VERSION 5.7 ;
  NOWIREEXTENSIONATPIN ON ;
  DIVIDERCHAR "/" ;
  BUSBITCHARS "[]" ;
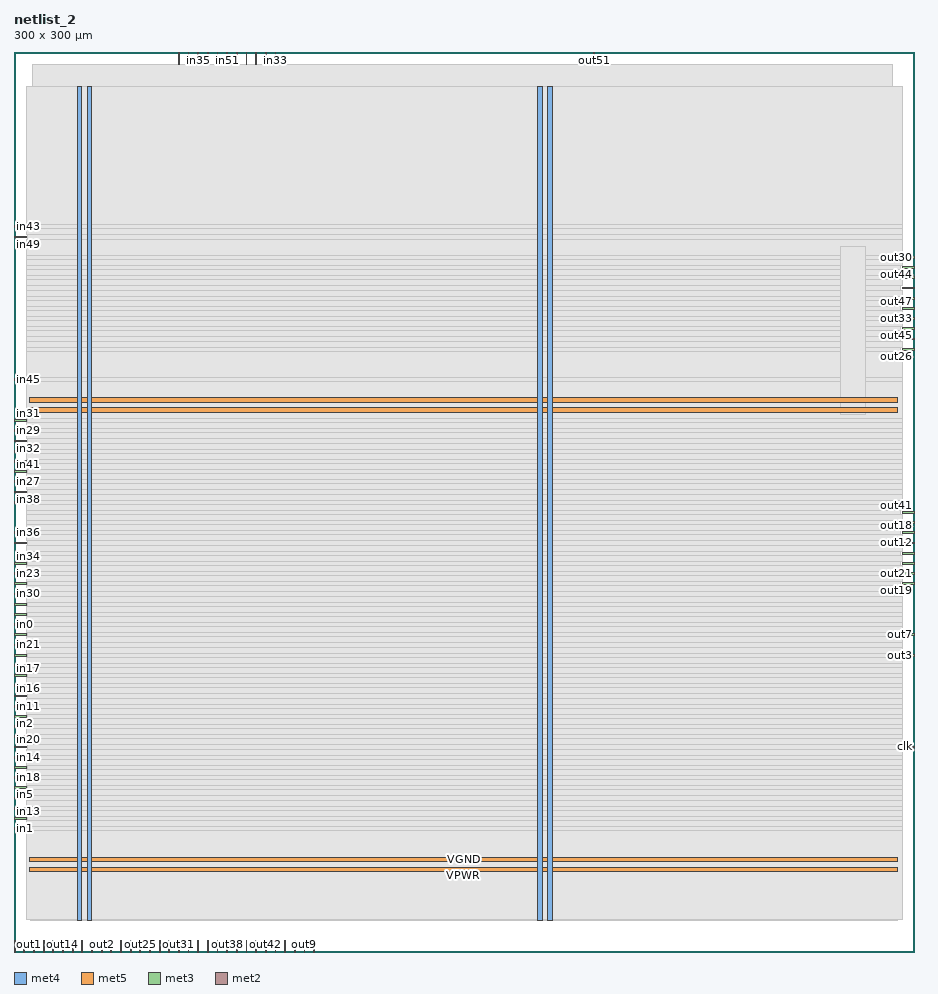
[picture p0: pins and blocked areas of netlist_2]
MACRO netlist_2
  CLASS BLOCK ;
  FOREIGN netlist_2 ;
  ORIGIN 0.000 0.000 ;
  SIZE 300.000 BY 300.000 ;
  PIN VGND
    DIRECTION INOUT ;
    USE GROUND ;
    PORT
      LAYER met4 ;
        RECT 24.340 10.640 25.940 288.560 ;
    END
    PORT
      LAYER met4 ;
        RECT 177.940 10.640 179.540 288.560 ;
    END
    PORT
      LAYER met5 ;
        RECT 5.280 30.030 294.640 31.630 ;
    END
    PORT
      LAYER met5 ;
        RECT 5.280 183.210 294.640 184.810 ;
    END
  END VGND
  PIN VPWR
    DIRECTION INOUT ;
    USE POWER ;
    PORT
      LAYER met4 ;
        RECT 21.040 10.640 22.640 288.560 ;
    END
    PORT
      LAYER met4 ;
        RECT 174.640 10.640 176.240 288.560 ;
    END
    PORT
      LAYER met5 ;
        RECT 5.280 26.730 294.640 28.330 ;
    END
    PORT
      LAYER met5 ;
        RECT 5.280 179.910 294.640 181.510 ;
    END
  END VPWR
  PIN clk
    DIRECTION INPUT ;
    USE SIGNAL ;
    ANTENNAGATEAREA 0.852000 ;
    ANTENNADIFFAREA 0.434700 ;
    PORT
      LAYER met3 ;
        RECT 296.000 68.040 300.000 68.640 ;
    END
  END clk
  PIN in0
    DIRECTION INPUT ;
    USE SIGNAL ;
    ANTENNAGATEAREA 0.196500 ;
    ANTENNADIFFAREA 0.434700 ;
    PORT
      LAYER met3 ;
        RECT 0.000 108.840 4.000 109.440 ;
    END
  END in0
  PIN in1
    DIRECTION INPUT ;
    USE SIGNAL ;
    ANTENNAGATEAREA 0.196500 ;
    ANTENNADIFFAREA 0.434700 ;
    PORT
      LAYER met3 ;
        RECT 0.000 40.840 4.000 41.440 ;
    END
  END in1
  PIN in10
    DIRECTION INPUT ;
    USE SIGNAL ;
    ANTENNAGATEAREA 0.196500 ;
    ANTENNADIFFAREA 0.434700 ;
    PORT
      LAYER met3 ;
        RECT 0.000 71.440 4.000 72.040 ;
    END
  END in10
  PIN in11
    DIRECTION INPUT ;
    USE SIGNAL ;
    ANTENNAGATEAREA 0.196500 ;
    ANTENNADIFFAREA 0.434700 ;
    PORT
      LAYER met3 ;
        RECT 0.000 81.640 4.000 82.240 ;
    END
  END in11
  PIN in12
    DIRECTION INPUT ;
    USE SIGNAL ;
    ANTENNAGATEAREA 0.196500 ;
    ANTENNADIFFAREA 0.434700 ;
    PORT
      LAYER met3 ;
        RECT 0.000 105.440 4.000 106.040 ;
    END
  END in12
  PIN in13
    DIRECTION INPUT ;
    USE SIGNAL ;
    ANTENNAGATEAREA 0.196500 ;
    ANTENNADIFFAREA 0.434700 ;
    PORT
      LAYER met3 ;
        RECT 0.000 44.240 4.000 44.840 ;
    END
  END in13
  PIN in14
    DIRECTION INPUT ;
    USE SIGNAL ;
    ANTENNAGATEAREA 0.196500 ;
    ANTENNADIFFAREA 0.434700 ;
    PORT
      LAYER met3 ;
        RECT 0.000 64.640 4.000 65.240 ;
    END
  END in14
  PIN in15
    DIRECTION INPUT ;
    USE SIGNAL ;
    ANTENNAGATEAREA 0.196500 ;
    ANTENNADIFFAREA 0.434700 ;
    PORT
      LAYER met3 ;
        RECT 0.000 88.440 4.000 89.040 ;
    END
  END in15
  PIN in16
    DIRECTION INPUT ;
    USE SIGNAL ;
    ANTENNAGATEAREA 0.196500 ;
    ANTENNADIFFAREA 0.434700 ;
    PORT
      LAYER met3 ;
        RECT 0.000 85.040 4.000 85.640 ;
    END
  END in16
  PIN in17
    DIRECTION INPUT ;
    USE SIGNAL ;
    ANTENNAGATEAREA 0.196500 ;
    ANTENNADIFFAREA 0.434700 ;
    PORT
      LAYER met3 ;
        RECT 0.000 91.840 4.000 92.440 ;
    END
  END in17
  PIN in18
    DIRECTION INPUT ;
    USE SIGNAL ;
    ANTENNAGATEAREA 0.196500 ;
    ANTENNADIFFAREA 0.434700 ;
    PORT
      LAYER met3 ;
        RECT 0.000 57.840 4.000 58.440 ;
    END
  END in18
  PIN in19
    DIRECTION INPUT ;
    USE SIGNAL ;
    ANTENNAGATEAREA 0.196500 ;
    ANTENNADIFFAREA 0.434700 ;
    PORT
      LAYER met3 ;
        RECT 0.000 61.240 4.000 61.840 ;
    END
  END in19
  PIN in2
    DIRECTION INPUT ;
    USE SIGNAL ;
    ANTENNAGATEAREA 0.196500 ;
    ANTENNADIFFAREA 0.434700 ;
    PORT
      LAYER met3 ;
        RECT 0.000 78.240 4.000 78.840 ;
    END
  END in2
  PIN in20
    DIRECTION INPUT ;
    USE SIGNAL ;
    ANTENNAGATEAREA 0.196500 ;
    ANTENNADIFFAREA 0.434700 ;
    PORT
      LAYER met3 ;
        RECT 0.000 68.040 4.000 68.640 ;
    END
  END in20
  PIN in21
    DIRECTION INPUT ;
    USE SIGNAL ;
    ANTENNAGATEAREA 0.196500 ;
    ANTENNADIFFAREA 0.434700 ;
    PORT
      LAYER met3 ;
        RECT 0.000 102.040 4.000 102.640 ;
    END
  END in21
  PIN in22
    DIRECTION INPUT ;
    USE SIGNAL ;
    ANTENNAGATEAREA 0.196500 ;
    ANTENNADIFFAREA 0.434700 ;
    PORT
      LAYER met3 ;
        RECT 0.000 122.440 4.000 123.040 ;
    END
  END in22
  PIN in23
    DIRECTION INPUT ;
    USE SIGNAL ;
    ANTENNAGATEAREA 0.196500 ;
    ANTENNADIFFAREA 0.434700 ;
    PORT
      LAYER met3 ;
        RECT 0.000 125.840 4.000 126.440 ;
    END
  END in23
  PIN in24
    DIRECTION INPUT ;
    USE SIGNAL ;
    ANTENNAGATEAREA 0.196500 ;
    ANTENNADIFFAREA 0.434700 ;
    PORT
      LAYER met2 ;
        RECT 74.150 296.000 74.430 300.000 ;
    END
  END in24
  PIN in25
    DIRECTION INPUT ;
    USE SIGNAL ;
    ANTENNAGATEAREA 0.196500 ;
    ANTENNADIFFAREA 0.434700 ;
    PORT
      LAYER met3 ;
        RECT 0.000 166.640 4.000 167.240 ;
    END
  END in25
  PIN in26
    DIRECTION INPUT ;
    USE SIGNAL ;
    ANTENNAGATEAREA 0.196500 ;
    ANTENNADIFFAREA 0.434700 ;
    PORT
      LAYER met3 ;
        RECT 0.000 112.240 4.000 112.840 ;
    END
  END in26
  PIN in27
    DIRECTION INPUT ;
    USE SIGNAL ;
    ANTENNAGATEAREA 0.196500 ;
    ANTENNADIFFAREA 0.434700 ;
    PORT
      LAYER met3 ;
        RECT 0.000 156.440 4.000 157.040 ;
    END
  END in27
  PIN in28
    DIRECTION INPUT ;
    USE SIGNAL ;
    ANTENNAGATEAREA 0.196500 ;
    ANTENNADIFFAREA 0.434700 ;
    PORT
      LAYER met3 ;
        RECT 0.000 149.640 4.000 150.240 ;
    END
  END in28
  PIN in29
    DIRECTION INPUT ;
    USE SIGNAL ;
    ANTENNAGATEAREA 0.196500 ;
    ANTENNADIFFAREA 0.434700 ;
    PORT
      LAYER met3 ;
        RECT 0.000 173.440 4.000 174.040 ;
    END
  END in29
  PIN in3
    DIRECTION INPUT ;
    USE SIGNAL ;
    ANTENNAGATEAREA 0.196500 ;
    ANTENNADIFFAREA 0.434700 ;
    PORT
      LAYER met3 ;
        RECT 0.000 98.640 4.000 99.240 ;
    END
  END in3
  PIN in30
    DIRECTION INPUT ;
    USE SIGNAL ;
    ANTENNAGATEAREA 0.196500 ;
    ANTENNADIFFAREA 0.434700 ;
    PORT
      LAYER met3 ;
        RECT 0.000 119.040 4.000 119.640 ;
    END
  END in30
  PIN in31
    DIRECTION INPUT ;
    USE SIGNAL ;
    ANTENNAGATEAREA 0.196500 ;
    ANTENNADIFFAREA 0.434700 ;
    PORT
      LAYER met3 ;
        RECT 0.000 176.840 4.000 177.440 ;
    END
  END in31
  PIN in32
    DIRECTION INPUT ;
    USE SIGNAL ;
    ANTENNAGATEAREA 0.196500 ;
    ANTENNADIFFAREA 0.434700 ;
    PORT
      LAYER met3 ;
        RECT 0.000 170.040 4.000 170.640 ;
    END
  END in32
  PIN in33
    DIRECTION INPUT ;
    USE SIGNAL ;
    ANTENNAGATEAREA 0.196500 ;
    ANTENNADIFFAREA 0.434700 ;
    PORT
      LAYER met2 ;
        RECT 87.030 296.000 87.310 300.000 ;
    END
  END in33
  PIN in34
    DIRECTION INPUT ;
    USE SIGNAL ;
    ANTENNAGATEAREA 0.196500 ;
    ANTENNADIFFAREA 0.434700 ;
    PORT
      LAYER met3 ;
        RECT 0.000 129.240 4.000 129.840 ;
    END
  END in34
  PIN in35
    DIRECTION INPUT ;
    USE SIGNAL ;
    ANTENNAGATEAREA 0.196500 ;
    ANTENNADIFFAREA 0.434700 ;
    PORT
      LAYER met2 ;
        RECT 61.270 296.000 61.550 300.000 ;
    END
  END in35
  PIN in36
    DIRECTION INPUT ;
    USE SIGNAL ;
    ANTENNAGATEAREA 0.196500 ;
    ANTENNADIFFAREA 0.434700 ;
    PORT
      LAYER met3 ;
        RECT 0.000 139.440 4.000 140.040 ;
    END
  END in36
  PIN in37
    DIRECTION INPUT ;
    USE SIGNAL ;
    ANTENNAGATEAREA 0.196500 ;
    ANTENNADIFFAREA 0.434700 ;
    PORT
      LAYER met3 ;
        RECT 0.000 115.640 4.000 116.240 ;
    END
  END in37
  PIN in38
    DIRECTION INPUT ;
    USE SIGNAL ;
    ANTENNAGATEAREA 0.196500 ;
    ANTENNADIFFAREA 0.434700 ;
    PORT
      LAYER met3 ;
        RECT 0.000 153.040 4.000 153.640 ;
    END
  END in38
  PIN in39
    DIRECTION INPUT ;
    USE SIGNAL ;
    ANTENNAGATEAREA 0.196500 ;
    ANTENNADIFFAREA 0.434700 ;
    PORT
      LAYER met2 ;
        RECT 58.050 296.000 58.330 300.000 ;
    END
  END in39
  PIN in4
    DIRECTION INPUT ;
    USE SIGNAL ;
    ANTENNAGATEAREA 0.196500 ;
    ANTENNADIFFAREA 0.434700 ;
    PORT
      LAYER met3 ;
        RECT 0.000 74.840 4.000 75.440 ;
    END
  END in4
  PIN in40
    DIRECTION INPUT ;
    USE SIGNAL ;
    ANTENNAGATEAREA 0.196500 ;
    ANTENNADIFFAREA 0.434700 ;
    PORT
      LAYER met3 ;
        RECT 0.000 163.240 4.000 163.840 ;
    END
  END in40
  PIN in41
    DIRECTION INPUT ;
    USE SIGNAL ;
    ANTENNAGATEAREA 0.196500 ;
    ANTENNADIFFAREA 0.434700 ;
    PORT
      LAYER met3 ;
        RECT 0.000 159.840 4.000 160.440 ;
    END
  END in41
  PIN in42
    DIRECTION INPUT ;
    USE SIGNAL ;
    ANTENNAGATEAREA 0.196500 ;
    ANTENNADIFFAREA 0.434700 ;
    PORT
      LAYER met3 ;
        RECT 0.000 136.040 4.000 136.640 ;
    END
  END in42
  PIN in43
    DIRECTION INPUT ;
    USE SIGNAL ;
    ANTENNAGATEAREA 0.196500 ;
    ANTENNADIFFAREA 0.434700 ;
    PORT
      LAYER met3 ;
        RECT 0.000 241.440 4.000 242.040 ;
    END
  END in43
  PIN in44
    DIRECTION INPUT ;
    USE SIGNAL ;
    ANTENNAGATEAREA 0.196500 ;
    ANTENNADIFFAREA 0.434700 ;
    PORT
      LAYER met2 ;
        RECT 80.590 296.000 80.870 300.000 ;
    END
  END in44
  PIN in45
    DIRECTION INPUT ;
    USE SIGNAL ;
    ANTENNAGATEAREA 0.196500 ;
    ANTENNADIFFAREA 0.434700 ;
    PORT
      LAYER met3 ;
        RECT 0.000 190.440 4.000 191.040 ;
    END
  END in45
  PIN in46
    DIRECTION INPUT ;
    USE SIGNAL ;
    ANTENNAGATEAREA 0.159000 ;
    ANTENNADIFFAREA 0.434700 ;
    PORT
      LAYER met2 ;
        RECT 67.710 296.000 67.990 300.000 ;
    END
  END in46
  PIN in47
    DIRECTION INPUT ;
    USE SIGNAL ;
    ANTENNAGATEAREA 0.213000 ;
    ANTENNADIFFAREA 0.434700 ;
    PORT
      LAYER met2 ;
        RECT 77.370 296.000 77.650 300.000 ;
    END
  END in47
  PIN in48
    DIRECTION INPUT ;
    USE SIGNAL ;
    ANTENNAGATEAREA 0.213000 ;
    ANTENNADIFFAREA 0.434700 ;
    PORT
      LAYER met2 ;
        RECT 54.830 296.000 55.110 300.000 ;
    END
  END in48
  PIN in49
    DIRECTION INPUT ;
    USE SIGNAL ;
    ANTENNAGATEAREA 0.196500 ;
    ANTENNADIFFAREA 0.434700 ;
    PORT
      LAYER met3 ;
        RECT 0.000 238.040 4.000 238.640 ;
    END
  END in49
  PIN in5
    DIRECTION INPUT ;
    USE SIGNAL ;
    ANTENNAGATEAREA 0.196500 ;
    ANTENNADIFFAREA 0.434700 ;
    PORT
      LAYER met3 ;
        RECT 0.000 54.440 4.000 55.040 ;
    END
  END in5
  PIN in50
    DIRECTION INPUT ;
    USE SIGNAL ;
    ANTENNAGATEAREA 0.196500 ;
    ANTENNADIFFAREA 0.434700 ;
    PORT
      LAYER met2 ;
        RECT 64.490 296.000 64.770 300.000 ;
    END
  END in50
  PIN in51
    DIRECTION INPUT ;
    USE SIGNAL ;
    ANTENNAGATEAREA 0.196500 ;
    ANTENNADIFFAREA 0.434700 ;
    PORT
      LAYER met2 ;
        RECT 70.930 296.000 71.210 300.000 ;
    END
  END in51
  PIN in6
    DIRECTION INPUT ;
    USE SIGNAL ;
    ANTENNAGATEAREA 0.196500 ;
    ANTENNADIFFAREA 0.434700 ;
    PORT
      LAYER met3 ;
        RECT 0.000 47.640 4.000 48.240 ;
    END
  END in6
  PIN in7
    DIRECTION INPUT ;
    USE SIGNAL ;
    ANTENNAGATEAREA 0.196500 ;
    ANTENNADIFFAREA 0.434700 ;
    PORT
      LAYER met3 ;
        RECT 0.000 51.040 4.000 51.640 ;
    END
  END in7
  PIN in8
    DIRECTION INPUT ;
    USE SIGNAL ;
    ANTENNAGATEAREA 0.196500 ;
    ANTENNADIFFAREA 0.434700 ;
    PORT
      LAYER met3 ;
        RECT 0.000 95.240 4.000 95.840 ;
    END
  END in8
  PIN in9
    DIRECTION INPUT ;
    USE SIGNAL ;
    ANTENNAGATEAREA 0.196500 ;
    ANTENNADIFFAREA 0.434700 ;
    PORT
      LAYER met2 ;
        RECT 83.810 296.000 84.090 300.000 ;
    END
  END in9
  PIN out0
    DIRECTION OUTPUT ;
    USE SIGNAL ;
    PORT
      LAYER met2 ;
        RECT 0.090 0.000 0.370 4.000 ;
    END
  END out0
  PIN out1
    DIRECTION OUTPUT ;
    USE SIGNAL ;
    PORT
      LAYER met2 ;
        RECT 3.310 0.000 3.590 4.000 ;
    END
  END out1
  PIN out10
    DIRECTION OUTPUT ;
    USE SIGNAL ;
    PORT
      LAYER met2 ;
        RECT 6.530 0.000 6.810 4.000 ;
    END
  END out10
  PIN out11
    DIRECTION OUTPUT ;
    USE SIGNAL ;
    PORT
      LAYER met2 ;
        RECT 9.750 0.000 10.030 4.000 ;
    END
  END out11
  PIN out12
    DIRECTION OUTPUT ;
    USE SIGNAL ;
    ANTENNADIFFAREA 0.445500 ;
    PORT
      LAYER met3 ;
        RECT 296.000 136.040 300.000 136.640 ;
    END
  END out12
  PIN out13
    DIRECTION OUTPUT ;
    USE SIGNAL ;
    PORT
      LAYER met2 ;
        RECT 12.970 0.000 13.250 4.000 ;
    END
  END out13
  PIN out14
    DIRECTION OUTPUT ;
    USE SIGNAL ;
    PORT
      LAYER met2 ;
        RECT 16.190 0.000 16.470 4.000 ;
    END
  END out14
  PIN out15
    DIRECTION OUTPUT ;
    USE SIGNAL ;
    PORT
      LAYER met2 ;
        RECT 19.410 0.000 19.690 4.000 ;
    END
  END out15
  PIN out16
    DIRECTION OUTPUT ;
    USE SIGNAL ;
    PORT
      LAYER met2 ;
        RECT 22.630 0.000 22.910 4.000 ;
    END
  END out16
  PIN out17
    DIRECTION OUTPUT ;
    USE SIGNAL ;
    PORT
      LAYER met2 ;
        RECT 25.850 0.000 26.130 4.000 ;
    END
  END out17
  PIN out18
    DIRECTION OUTPUT ;
    USE SIGNAL ;
    ANTENNADIFFAREA 0.445500 ;
    PORT
      LAYER met3 ;
        RECT 296.000 139.440 300.000 140.040 ;
    END
  END out18
  PIN out19
    DIRECTION OUTPUT ;
    USE SIGNAL ;
    ANTENNADIFFAREA 0.445500 ;
    PORT
      LAYER met3 ;
        RECT 296.000 122.440 300.000 123.040 ;
    END
  END out19
  PIN out2
    DIRECTION OUTPUT ;
    USE SIGNAL ;
    PORT
      LAYER met2 ;
        RECT 29.070 0.000 29.350 4.000 ;
    END
  END out2
  PIN out20
    DIRECTION OUTPUT ;
    USE SIGNAL ;
    PORT
      LAYER met2 ;
        RECT 32.290 0.000 32.570 4.000 ;
    END
  END out20
  PIN out21
    DIRECTION OUTPUT ;
    USE SIGNAL ;
    ANTENNADIFFAREA 0.445500 ;
    PORT
      LAYER met3 ;
        RECT 296.000 125.840 300.000 126.440 ;
    END
  END out21
  PIN out22
    DIRECTION OUTPUT ;
    USE SIGNAL ;
    PORT
      LAYER met2 ;
        RECT 35.510 0.000 35.790 4.000 ;
    END
  END out22
  PIN out23
    DIRECTION OUTPUT ;
    USE SIGNAL ;
    ANTENNADIFFAREA 0.445500 ;
    PORT
      LAYER met3 ;
        RECT 296.000 142.840 300.000 143.440 ;
    END
  END out23
  PIN out24
    DIRECTION OUTPUT ;
    USE SIGNAL ;
    PORT
      LAYER met2 ;
        RECT 38.730 0.000 39.010 4.000 ;
    END
  END out24
  PIN out25
    DIRECTION OUTPUT ;
    USE SIGNAL ;
    PORT
      LAYER met2 ;
        RECT 41.950 0.000 42.230 4.000 ;
    END
  END out25
  PIN out26
    DIRECTION OUTPUT ;
    USE SIGNAL ;
    ANTENNADIFFAREA 0.340600 ;
    PORT
      LAYER met3 ;
        RECT 296.000 200.640 300.000 201.240 ;
    END
  END out26
  PIN out27
    DIRECTION OUTPUT ;
    USE SIGNAL ;
    PORT
      LAYER met2 ;
        RECT 45.170 0.000 45.450 4.000 ;
    END
  END out27
  PIN out28
    DIRECTION OUTPUT ;
    USE SIGNAL ;
    PORT
      LAYER met2 ;
        RECT 48.390 0.000 48.670 4.000 ;
    END
  END out28
  PIN out29
    DIRECTION OUTPUT ;
    USE SIGNAL ;
    PORT
      LAYER met2 ;
        RECT 51.610 0.000 51.890 4.000 ;
    END
  END out29
  PIN out3
    DIRECTION OUTPUT ;
    USE SIGNAL ;
    ANTENNADIFFAREA 0.445500 ;
    PORT
      LAYER met3 ;
        RECT 296.000 98.640 300.000 99.240 ;
    END
  END out3
  PIN out30
    DIRECTION OUTPUT ;
    USE SIGNAL ;
    ANTENNADIFFAREA 0.340600 ;
    PORT
      LAYER met3 ;
        RECT 296.000 231.240 300.000 231.840 ;
    END
  END out30
  PIN out31
    DIRECTION OUTPUT ;
    USE SIGNAL ;
    PORT
      LAYER met2 ;
        RECT 54.830 0.000 55.110 4.000 ;
    END
  END out31
  PIN out32
    DIRECTION OUTPUT ;
    USE SIGNAL ;
    PORT
      LAYER met2 ;
        RECT 58.050 0.000 58.330 4.000 ;
    END
  END out32
  PIN out33
    DIRECTION OUTPUT ;
    USE SIGNAL ;
    ANTENNADIFFAREA 0.340600 ;
    PORT
      LAYER met3 ;
        RECT 296.000 210.840 300.000 211.440 ;
    END
  END out33
  PIN out34
    DIRECTION OUTPUT ;
    USE SIGNAL ;
    PORT
      LAYER met2 ;
        RECT 61.270 0.000 61.550 4.000 ;
    END
  END out34
  PIN out35
    DIRECTION OUTPUT ;
    USE SIGNAL ;
    ANTENNADIFFAREA 0.445500 ;
    PORT
      LAYER met3 ;
        RECT 296.000 132.640 300.000 133.240 ;
    END
  END out35
  PIN out36
    DIRECTION OUTPUT ;
    USE SIGNAL ;
    PORT
      LAYER met2 ;
        RECT 64.490 0.000 64.770 4.000 ;
    END
  END out36
  PIN out37
    DIRECTION OUTPUT ;
    USE SIGNAL ;
    PORT
      LAYER met2 ;
        RECT 67.710 0.000 67.990 4.000 ;
    END
  END out37
  PIN out38
    DIRECTION OUTPUT ;
    USE SIGNAL ;
    PORT
      LAYER met2 ;
        RECT 70.930 0.000 71.210 4.000 ;
    END
  END out38
  PIN out39
    DIRECTION OUTPUT ;
    USE SIGNAL ;
    PORT
      LAYER met2 ;
        RECT 74.150 0.000 74.430 4.000 ;
    END
  END out39
  PIN out4
    DIRECTION OUTPUT ;
    USE SIGNAL ;
    PORT
      LAYER met2 ;
        RECT 77.370 0.000 77.650 4.000 ;
    END
  END out4
  PIN out40
    DIRECTION OUTPUT ;
    USE SIGNAL ;
    PORT
      LAYER met2 ;
        RECT 80.590 0.000 80.870 4.000 ;
    END
  END out40
  PIN out41
    DIRECTION OUTPUT ;
    USE SIGNAL ;
    ANTENNADIFFAREA 0.445500 ;
    PORT
      LAYER met3 ;
        RECT 296.000 146.240 300.000 146.840 ;
    END
  END out41
  PIN out42
    DIRECTION OUTPUT ;
    USE SIGNAL ;
    PORT
      LAYER met2 ;
        RECT 83.810 0.000 84.090 4.000 ;
    END
  END out42
  PIN out43
    DIRECTION OUTPUT ;
    USE SIGNAL ;
    PORT
      LAYER met2 ;
        RECT 87.030 0.000 87.310 4.000 ;
    END
  END out43
  PIN out44
    DIRECTION OUTPUT ;
    USE SIGNAL ;
    ANTENNADIFFAREA 0.340600 ;
    PORT
      LAYER met3 ;
        RECT 296.000 227.840 300.000 228.440 ;
    END
  END out44
  PIN out45
    DIRECTION OUTPUT ;
    USE SIGNAL ;
    ANTENNADIFFAREA 0.340600 ;
    PORT
      LAYER met3 ;
        RECT 296.000 207.440 300.000 208.040 ;
    END
  END out45
  PIN out46
    DIRECTION OUTPUT ;
    USE SIGNAL ;
    ANTENNADIFFAREA 0.340600 ;
    PORT
      LAYER met3 ;
        RECT 296.000 217.640 300.000 218.240 ;
    END
  END out46
  PIN out47
    DIRECTION OUTPUT ;
    USE SIGNAL ;
    ANTENNADIFFAREA 0.340600 ;
    PORT
      LAYER met3 ;
        RECT 296.000 214.240 300.000 214.840 ;
    END
  END out47
  PIN out48
    DIRECTION OUTPUT ;
    USE SIGNAL ;
    ANTENNADIFFAREA 0.445500 ;
    PORT
      LAYER met3 ;
        RECT 296.000 204.040 300.000 204.640 ;
    END
  END out48
  PIN out49
    DIRECTION OUTPUT ;
    USE SIGNAL ;
    ANTENNADIFFAREA 1.782000 ;
    PORT
      LAYER met3 ;
        RECT 296.000 224.440 300.000 225.040 ;
    END
  END out49
  PIN out5
    DIRECTION OUTPUT ;
    USE SIGNAL ;
    ANTENNADIFFAREA 0.445500 ;
    PORT
      LAYER met3 ;
        RECT 296.000 129.240 300.000 129.840 ;
    END
  END out5
  PIN out50
    DIRECTION OUTPUT ;
    USE SIGNAL ;
    ANTENNADIFFAREA 0.340600 ;
    PORT
      LAYER met3 ;
        RECT 296.000 221.040 300.000 221.640 ;
    END
  END out50
  PIN out51
    DIRECTION OUTPUT ;
    USE SIGNAL ;
    ANTENNADIFFAREA 0.445500 ;
    PORT
      LAYER met2 ;
        RECT 193.290 296.000 193.570 300.000 ;
    END
  END out51
  PIN out6
    DIRECTION OUTPUT ;
    USE SIGNAL ;
    PORT
      LAYER met2 ;
        RECT 90.250 0.000 90.530 4.000 ;
    END
  END out6
  PIN out7
    DIRECTION OUTPUT ;
    USE SIGNAL ;
    ANTENNADIFFAREA 0.445500 ;
    PORT
      LAYER met3 ;
        RECT 296.000 105.440 300.000 106.040 ;
    END
  END out7
  PIN out8
    DIRECTION OUTPUT ;
    USE SIGNAL ;
    PORT
      LAYER met2 ;
        RECT 93.470 0.000 93.750 4.000 ;
    END
  END out8
  PIN out9
    DIRECTION OUTPUT ;
    USE SIGNAL ;
    PORT
      LAYER met2 ;
        RECT 96.690 0.000 96.970 4.000 ;
    END
  END out9
  PIN rst
    DIRECTION INPUT ;
    USE SIGNAL ;
    PORT
      LAYER met2 ;
        RECT 99.910 0.000 100.190 4.000 ;
    END
  END rst
  OBS
      LAYER li1 ;
        RECT 5.520 10.795 294.400 288.405 ;
      LAYER met1 ;
        RECT 5.520 10.640 294.400 288.560 ;
      LAYER met2 ;
        RECT 6.070 295.720 54.550 296.000 ;
        RECT 55.390 295.720 57.770 296.000 ;
        RECT 58.610 295.720 60.990 296.000 ;
        RECT 61.830 295.720 64.210 296.000 ;
        RECT 65.050 295.720 67.430 296.000 ;
        RECT 68.270 295.720 70.650 296.000 ;
        RECT 71.490 295.720 73.870 296.000 ;
        RECT 74.710 295.720 77.090 296.000 ;
        RECT 77.930 295.720 80.310 296.000 ;
        RECT 81.150 295.720 83.530 296.000 ;
        RECT 84.370 295.720 86.750 296.000 ;
        RECT 87.590 295.720 193.010 296.000 ;
        RECT 193.850 295.720 292.930 296.000 ;
        RECT 6.070 10.695 292.930 295.720 ;
      LAYER met3 ;
        RECT 4.000 242.440 296.000 288.485 ;
        RECT 4.400 241.040 296.000 242.440 ;
        RECT 4.000 239.040 296.000 241.040 ;
        RECT 4.400 237.640 296.000 239.040 ;
        RECT 4.000 232.240 296.000 237.640 ;
        RECT 4.000 230.840 295.600 232.240 ;
        RECT 4.000 228.840 296.000 230.840 ;
        RECT 4.000 227.440 295.600 228.840 ;
        RECT 4.000 225.440 296.000 227.440 ;
        RECT 4.000 224.040 295.600 225.440 ;
        RECT 4.000 222.040 296.000 224.040 ;
        RECT 4.000 220.640 295.600 222.040 ;
        RECT 4.000 218.640 296.000 220.640 ;
        RECT 4.000 217.240 295.600 218.640 ;
        RECT 4.000 215.240 296.000 217.240 ;
        RECT 4.000 213.840 295.600 215.240 ;
        RECT 4.000 211.840 296.000 213.840 ;
        RECT 4.000 210.440 295.600 211.840 ;
        RECT 4.000 208.440 296.000 210.440 ;
        RECT 4.000 207.040 295.600 208.440 ;
        RECT 4.000 205.040 296.000 207.040 ;
        RECT 4.000 203.640 295.600 205.040 ;
        RECT 4.000 201.640 296.000 203.640 ;
        RECT 4.000 200.240 295.600 201.640 ;
        RECT 4.000 191.440 296.000 200.240 ;
        RECT 4.400 190.040 296.000 191.440 ;
        RECT 4.000 177.840 296.000 190.040 ;
        RECT 4.400 176.440 296.000 177.840 ;
        RECT 4.000 174.440 296.000 176.440 ;
        RECT 4.400 173.040 296.000 174.440 ;
        RECT 4.000 171.040 296.000 173.040 ;
        RECT 4.400 169.640 296.000 171.040 ;
        RECT 4.000 167.640 296.000 169.640 ;
        RECT 4.400 166.240 296.000 167.640 ;
        RECT 4.000 164.240 296.000 166.240 ;
        RECT 4.400 162.840 296.000 164.240 ;
        RECT 4.000 160.840 296.000 162.840 ;
        RECT 4.400 159.440 296.000 160.840 ;
        RECT 4.000 157.440 296.000 159.440 ;
        RECT 4.400 156.040 296.000 157.440 ;
        RECT 4.000 154.040 296.000 156.040 ;
        RECT 4.400 152.640 296.000 154.040 ;
        RECT 4.000 150.640 296.000 152.640 ;
        RECT 4.400 149.240 296.000 150.640 ;
        RECT 4.000 147.240 296.000 149.240 ;
        RECT 4.000 145.840 295.600 147.240 ;
        RECT 4.000 143.840 296.000 145.840 ;
        RECT 4.000 142.440 295.600 143.840 ;
        RECT 4.000 140.440 296.000 142.440 ;
        RECT 4.400 139.040 295.600 140.440 ;
        RECT 4.000 137.040 296.000 139.040 ;
        RECT 4.400 135.640 295.600 137.040 ;
        RECT 4.000 133.640 296.000 135.640 ;
        RECT 4.000 132.240 295.600 133.640 ;
        RECT 4.000 130.240 296.000 132.240 ;
        RECT 4.400 128.840 295.600 130.240 ;
        RECT 4.000 126.840 296.000 128.840 ;
        RECT 4.400 125.440 295.600 126.840 ;
        RECT 4.000 123.440 296.000 125.440 ;
        RECT 4.400 122.040 295.600 123.440 ;
        RECT 4.000 120.040 296.000 122.040 ;
        RECT 4.400 118.640 296.000 120.040 ;
        RECT 4.000 116.640 296.000 118.640 ;
        RECT 4.400 115.240 296.000 116.640 ;
        RECT 4.000 113.240 296.000 115.240 ;
        RECT 4.400 111.840 296.000 113.240 ;
        RECT 4.000 109.840 296.000 111.840 ;
        RECT 4.400 108.440 296.000 109.840 ;
        RECT 4.000 106.440 296.000 108.440 ;
        RECT 4.400 105.040 295.600 106.440 ;
        RECT 4.000 103.040 296.000 105.040 ;
        RECT 4.400 101.640 296.000 103.040 ;
        RECT 4.000 99.640 296.000 101.640 ;
        RECT 4.400 98.240 295.600 99.640 ;
        RECT 4.000 96.240 296.000 98.240 ;
        RECT 4.400 94.840 296.000 96.240 ;
        RECT 4.000 92.840 296.000 94.840 ;
        RECT 4.400 91.440 296.000 92.840 ;
        RECT 4.000 89.440 296.000 91.440 ;
        RECT 4.400 88.040 296.000 89.440 ;
        RECT 4.000 86.040 296.000 88.040 ;
        RECT 4.400 84.640 296.000 86.040 ;
        RECT 4.000 82.640 296.000 84.640 ;
        RECT 4.400 81.240 296.000 82.640 ;
        RECT 4.000 79.240 296.000 81.240 ;
        RECT 4.400 77.840 296.000 79.240 ;
        RECT 4.000 75.840 296.000 77.840 ;
        RECT 4.400 74.440 296.000 75.840 ;
        RECT 4.000 72.440 296.000 74.440 ;
        RECT 4.400 71.040 296.000 72.440 ;
        RECT 4.000 69.040 296.000 71.040 ;
        RECT 4.400 67.640 295.600 69.040 ;
        RECT 4.000 65.640 296.000 67.640 ;
        RECT 4.400 64.240 296.000 65.640 ;
        RECT 4.000 62.240 296.000 64.240 ;
        RECT 4.400 60.840 296.000 62.240 ;
        RECT 4.000 58.840 296.000 60.840 ;
        RECT 4.400 57.440 296.000 58.840 ;
        RECT 4.000 55.440 296.000 57.440 ;
        RECT 4.400 54.040 296.000 55.440 ;
        RECT 4.000 52.040 296.000 54.040 ;
        RECT 4.400 50.640 296.000 52.040 ;
        RECT 4.000 48.640 296.000 50.640 ;
        RECT 4.400 47.240 296.000 48.640 ;
        RECT 4.000 45.240 296.000 47.240 ;
        RECT 4.400 43.840 296.000 45.240 ;
        RECT 4.000 41.840 296.000 43.840 ;
        RECT 4.400 40.440 296.000 41.840 ;
        RECT 4.000 10.715 296.000 40.440 ;
      LAYER met4 ;
        RECT 275.375 179.015 283.985 235.105 ;
  END
END netlist_2
END LIBRARY

